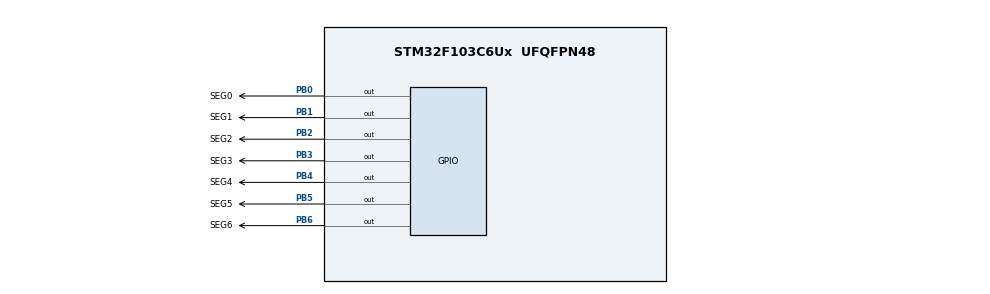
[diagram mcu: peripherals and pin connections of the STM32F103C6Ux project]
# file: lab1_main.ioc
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Mcu.Family=STM32F1
Mcu.Name=STM32F103C6Ux
Mcu.Package=UFQFPN48
NVIC.PriorityGroup=NVIC_PRIORITYGROUP_4
PB0.GPIO_Label=SEG0
PB0.Signal=GPIO_Output
PB1.GPIO_Label=SEG1
PB1.Signal=GPIO_Output
PB2.GPIO_Label=SEG2
PB2.Signal=GPIO_Output
PB3.GPIO_Label=SEG3
PB3.Signal=GPIO_Output
PB4.GPIO_Label=SEG4
PB4.Signal=GPIO_Output
PB5.GPIO_Label=SEG5
PB5.Signal=GPIO_Output
PB6.GPIO_Label=SEG6
PB6.Signal=GPIO_Output
ProjectManager.HeapSize=0x200
ProjectManager.StackSize=0x400
ProjectManager.TargetToolchain=STM32CubeIDE
RCC.APB1Freq_Value=8000000
RCC.APB2Freq_Value=8000000
VP_SYS_VS_ND.Mode=No_Debug
board=custom

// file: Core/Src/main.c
/* USER CODE BEGIN Header */
/**
  ******************************************************************************
  * @file           : main.c
  * @brief          : Main program body
  ******************************************************************************
  * @attention
  *
  * <h2><center>&copy; Copyright (c) 2023 STMicroelectronics.
  * All rights reserved.</center></h2>
  *
  * This software component is licensed by ST under BSD 3-Clause license,
  * the "License"; You may not use this file except in compliance with the
  * License. You may obtain a copy of the License at:
  *                        opensource.org/licenses/BSD-3-Clause
  *
  ******************************************************************************
  */
/* USER CODE END Header */
#include "main.h"

void SystemClock_Config(void);
static void MX_GPIO_Init(void);

void display7SEG(int num, uint16_t *pins){

	switch(num){
	case 0:
		HAL_GPIO_WritePin(GPIOB, pins[0], GPIO_PIN_RESET);
		HAL_GPIO_WritePin(GPIOB, pins[1], GPIO_PIN_RESET);
		HAL_GPIO_WritePin(GPIOB, pins[2], GPIO_PIN_RESET);
		HAL_GPIO_WritePin(GPIOB, pins[3], GPIO_PIN_RESET);
		HAL_GPIO_WritePin(GPIOB, pins[4], GPIO_PIN_RESET);
		HAL_GPIO_WritePin(GPIOB, pins[5], GPIO_PIN_RESET);
		HAL_GPIO_WritePin(GPIOB, pins[6], GPIO_PIN_SET);
		break;
	case 1:
		HAL_GPIO_WritePin(GPIOB, pins[0], GPIO_PIN_SET);
		HAL_GPIO_WritePin(GPIOB, pins[1], GPIO_PIN_RESET);
		HAL_GPIO_WritePin(GPIOB, pins[2], GPIO_PIN_RESET);
		HAL_GPIO_WritePin(GPIOB, pins[3], GPIO_PIN_SET);
		HAL_GPIO_WritePin(GPIOB, pins[4], GPIO_PIN_SET);
		HAL_GPIO_WritePin(GPIOB, pins[5], GPIO_PIN_SET);
		HAL_GPIO_WritePin(GPIOB, pins[6], GPIO_PIN_SET);
		break;
	case 2:
		HAL_GPIO_WritePin(GPIOB, pins[0], GPIO_PIN_RESET);
		HAL_GPIO_WritePin(GPIOB, pins[1], GPIO_PIN_RESET);
		HAL_GPIO_WritePin(GPIOB, pins[2], GPIO_PIN_SET);
		HAL_GPIO_WritePin(GPIOB, pins[3], GPIO_PIN_RESET);
		HAL_GPIO_WritePin(GPIOB, pins[4], GPIO_PIN_RESET);
		HAL_GPIO_WritePin(GPIOB, pins[5], GPIO_PIN_SET);
		HAL_GPIO_WritePin(GPIOB, pins[6], GPIO_PIN_RESET);
		break;
	case 3:
		HAL_GPIO_WritePin(GPIOB, pins[0], GPIO_PIN_RESET);
		HAL_GPIO_WritePin(GPIOB, pins[1], GPIO_PIN_RESET);
		HAL_GPIO_WritePin(GPIOB, pins[2], GPIO_PIN_RESET);
		HAL_GPIO_WritePin(GPIOB, pins[3], GPIO_PIN_RESET);
		HAL_GPIO_WritePin(GPIOB, pins[4], GPIO_PIN_SET);
		HAL_GPIO_WritePin(GPIOB, pins[5], GPIO_PIN_SET);
		HAL_GPIO_WritePin(GPIOB, pins[6], GPIO_PIN_RESET);
		break;
	case 4:
		HAL_GPIO_WritePin(GPIOB, pins[0], GPIO_PIN_SET);
		HAL_GPIO_WritePin(GPIOB, pins[1], GPIO_PIN_RESET);
		HAL_GPIO_WritePin(GPIOB, pins[2], GPIO_PIN_RESET);
		HAL_GPIO_WritePin(GPIOB, pins[3], GPIO_PIN_SET);
		HAL_GPIO_WritePin(GPIOB, pins[4], GPIO_PIN_SET);
		HAL_GPIO_WritePin(GPIOB, pins[5], GPIO_PIN_RESET);
		HAL_GPIO_WritePin(GPIOB, pins[6], GPIO_PIN_RESET);
		break;
	case 5:
		HAL_GPIO_WritePin(GPIOB, pins[0], GPIO_PIN_RESET);
		HAL_GPIO_WritePin(GPIOB, pins[1], GPIO_PIN_SET);
		HAL_GPIO_WritePin(GPIOB, pins[2], GPIO_PIN_RESET);
		HAL_GPIO_WritePin(GPIOB, pins[3], GPIO_PIN_RESET);
		HAL_GPIO_WritePin(GPIOB, pins[4], GPIO_PIN_SET);
		HAL_GPIO_WritePin(GPIOB, pins[5], GPIO_PIN_RESET);
		HAL_GPIO_WritePin(GPIOB, pins[6], GPIO_PIN_RESET);
		break;
	case 6:
		HAL_GPIO_WritePin(GPIOB, pins[0], GPIO_PIN_RESET);
		HAL_GPIO_WritePin(GPIOB, pins[1], GPIO_PIN_SET);
		HAL_GPIO_WritePin(GPIOB, pins[2], GPIO_PIN_RESET);
		HAL_GPIO_WritePin(GPIOB, pins[3], GPIO_PIN_RESET);
		HAL_GPIO_WritePin(GPIOB, pins[4], GPIO_PIN_RESET);
		HAL_GPIO_WritePin(GPIOB, pins[5], GPIO_PIN_RESET);
		HAL_GPIO_WritePin(GPIOB, pins[6], GPIO_PIN_RESET);
		break;
	case 7:
		HAL_GPIO_WritePin(GPIOB, pins[0], GPIO_PIN_RESET);
		HAL_GPIO_WritePin(GPIOB, pins[1], GPIO_PIN_RESET);
		HAL_GPIO_WritePin(GPIOB, pins[2], GPIO_PIN_RESET);
		HAL_GPIO_WritePin(GPIOB, pins[3], GPIO_PIN_SET);
		HAL_GPIO_WritePin(GPIOB, pins[4], GPIO_PIN_SET);
		HAL_GPIO_WritePin(GPIOB, pins[5], GPIO_PIN_SET);
		HAL_GPIO_WritePin(GPIOB, pins[6], GPIO_PIN_SET);
		break;
	case 8:
		HAL_GPIO_WritePin(GPIOB, pins[0], GPIO_PIN_RESET);
		HAL_GPIO_WritePin(GPIOB, pins[1], GPIO_PIN_RESET);
		HAL_GPIO_WritePin(GPIOB, pins[2], GPIO_PIN_RESET);
		HAL_GPIO_WritePin(GPIOB, pins[3], GPIO_PIN_RESET);
		HAL_GPIO_WritePin(GPIOB, pins[4], GPIO_PIN_RESET);
		HAL_GPIO_WritePin(GPIOB, pins[5], GPIO_PIN_RESET);
		HAL_GPIO_WritePin(GPIOB, pins[6], GPIO_PIN_RESET);
		break;
	case 9:
		HAL_GPIO_WritePin(GPIOB, pins[0], GPIO_PIN_RESET);
		HAL_GPIO_WritePin(GPIOB, pins[1], GPIO_PIN_RESET);
		HAL_GPIO_WritePin(GPIOB, pins[2], GPIO_PIN_RESET);
		HAL_GPIO_WritePin(GPIOB, pins[3], GPIO_PIN_RESET);
		HAL_GPIO_WritePin(GPIOB, pins[4], GPIO_PIN_SET);
		HAL_GPIO_WritePin(GPIOB, pins[5], GPIO_PIN_RESET);
		HAL_GPIO_WritePin(GPIOB, pins[6], GPIO_PIN_RESET);
		break;
	default:
		break;
	}
}
int main(void)
{

  /* MCU Configuration--------------------------------------------------------*/

  /* Reset of all peripherals, Initializes the Flash interface and the Systick. */
  HAL_Init();

  /* Configure the system clock */
  SystemClock_Config();

  /* Initialize all configured peripherals */
  MX_GPIO_Init();

  /* Infinite loop */
  /* USER CODE BEGIN WHILE */
  enum lightState {RED1_GREEN2, RED1_YELLOW2, GREEN1_RED2, YELLOW1_RED2,};
  enum lightState curr_state = RED1_GREEN2;
  enum lightState next_state = curr_state;
  uint16_t p_pins[7] = {P0_Pin, P1_Pin, P2_Pin, P3_Pin, P4_Pin, P5_Pin, P6_Pin};
  uint16_t l_pins[7] = {L0_Pin, L1_Pin, L2_Pin, L3_Pin, L4_Pin, L5_Pin, L6_Pin};
  int l_count = 4, p_count = 2, count = 3;
  HAL_GPIO_WritePin(GPIOA, RED1_Pin, SET);
  HAL_GPIO_WritePin(GPIOA, YELLOW1_Pin, SET);
  HAL_GPIO_WritePin(GPIOA, GREEN1_Pin, SET);
  HAL_GPIO_WritePin(GPIOA, RED2_Pin, SET);
  HAL_GPIO_WritePin(GPIOA, YELLOW2_Pin, SET);
  HAL_GPIO_WritePin(GPIOA, GREEN2_Pin, SET);
   while (1)
   {
	   display7SEG(l_count, l_pins);
	   display7SEG(p_count, p_pins);
	   if(count > 0) count --;
	   if(l_count > 0) l_count --;
	   if(p_count > 0) p_count --;
	  switch(curr_state){
	  case RED1_GREEN2:
		  HAL_GPIO_WritePin(RED1_GPIO_Port, RED1_Pin, GPIO_PIN_RESET);
		  HAL_GPIO_WritePin(YELLOW1_GPIO_Port, YELLOW1_Pin, GPIO_PIN_SET);
		  HAL_GPIO_WritePin(GREEN1_GPIO_Port, GREEN1_Pin, GPIO_PIN_SET);
		  HAL_GPIO_WritePin(RED2_GPIO_Port, RED2_Pin, GPIO_PIN_SET);
		  HAL_GPIO_WritePin(YELLOW2_GPIO_Port, YELLOW2_Pin, GPIO_PIN_SET);
		  HAL_GPIO_WritePin(GREEN2_GPIO_Port, GREEN2_Pin, GPIO_PIN_RESET);
		  if(count <= 0){
			  count = 2;
			  next_state = RED1_YELLOW2;
			  p_count = 1;
		  }
		  break;
	  case RED1_YELLOW2:
		  HAL_GPIO_WritePin(RED1_GPIO_Port, RED1_Pin, GPIO_PIN_RESET);
		  HAL_GPIO_WritePin(YELLOW1_GPIO_Port, YELLOW1_Pin, GPIO_PIN_SET);
		  HAL_GPIO_WritePin(GREEN1_GPIO_Port, GREEN1_Pin, GPIO_PIN_SET);
		  HAL_GPIO_WritePin(RED2_GPIO_Port, RED2_Pin, GPIO_PIN_SET);
		  HAL_GPIO_WritePin(YELLOW2_GPIO_Port, YELLOW2_Pin, GPIO_PIN_RESET);
		  HAL_GPIO_WritePin(GREEN2_GPIO_Port, GREEN2_Pin, GPIO_PIN_SET);
		  if(count <= 0){
			  count = 3;
			  next_state = GREEN1_RED2;
			  p_count = 4;
			  l_count = 2;
		  }
		  break;
	  case GREEN1_RED2:
		  HAL_GPIO_WritePin(RED1_GPIO_Port, RED1_Pin, GPIO_PIN_SET);
		  HAL_GPIO_WritePin(YELLOW1_GPIO_Port, YELLOW1_Pin, GPIO_PIN_SET);
		  HAL_GPIO_WritePin(GREEN1_GPIO_Port, GREEN1_Pin, GPIO_PIN_RESET);
		  HAL_GPIO_WritePin(RED2_GPIO_Port, RED2_Pin, GPIO_PIN_RESET);
		  HAL_GPIO_WritePin(YELLOW2_GPIO_Port, YELLOW2_Pin, GPIO_PIN_SET);
		  HAL_GPIO_WritePin(GREEN2_GPIO_Port, GREEN2_Pin, GPIO_PIN_SET);
		  if(count <= 0){
			  count = 2;
			  next_state = YELLOW1_RED2;
			  l_count = 1;
		  }
		  break;
	  case YELLOW1_RED2:
		  HAL_GPIO_WritePin(RED1_GPIO_Port, RED1_Pin, GPIO_PIN_SET);
		  HAL_GPIO_WritePin(YELLOW1_GPIO_Port, YELLOW1_Pin, GPIO_PIN_RESET);
		  HAL_GPIO_WritePin(GREEN1_GPIO_Port, GREEN1_Pin, GPIO_PIN_SET);
		  HAL_GPIO_WritePin(RED2_GPIO_Port, RED2_Pin, GPIO_PIN_RESET);
		  HAL_GPIO_WritePin(YELLOW2_GPIO_Port, YELLOW2_Pin, GPIO_PIN_SET);
		  HAL_GPIO_WritePin(GREEN2_GPIO_Port, GREEN2_Pin, GPIO_PIN_SET);
		  if(count <= 0){
			  count = 3;
			  next_state = RED1_GREEN2;
			  p_count = 2;
			  l_count = 4;
		  }
		  break;
	  default:
		  break;
	  }
	  curr_state = next_state;
	 HAL_Delay(1000);
    /* USER CODE END WHILE */

  }
}

void SystemClock_Config(void)
{
  RCC_OscInitTypeDef RCC_OscInitStruct = {0};
  RCC_ClkInitTypeDef RCC_ClkInitStruct = {0};

  /** Initializes the RCC Oscillators according to the specified parameters
  * in the RCC_OscInitTypeDef structure.
  */
  RCC_OscInitStruct.OscillatorType = RCC_OSCILLATORTYPE_HSI;
  RCC_OscInitStruct.HSIState = RCC_HSI_ON;
  RCC_OscInitStruct.HSICalibrationValue = RCC_HSICALIBRATION_DEFAULT;
  RCC_OscInitStruct.PLL.PLLState = RCC_PLL_NONE;
  if (HAL_RCC_OscConfig(&RCC_OscInitStruct) != HAL_OK)
  {
    Error_Handler();
  }
  /** Initializes the CPU, AHB and APB buses clocks
  */
  RCC_ClkInitStruct.ClockType = RCC_CLOCKTYPE_HCLK|RCC_CLOCKTYPE_SYSCLK
                              |RCC_CLOCKTYPE_PCLK1|RCC_CLOCKTYPE_PCLK2;
  RCC_ClkInitStruct.SYSCLKSource = RCC_SYSCLKSOURCE_HSI;
  RCC_ClkInitStruct.AHBCLKDivider = RCC_SYSCLK_DIV1;
  RCC_ClkInitStruct.APB1CLKDivider = RCC_HCLK_DIV1;
  RCC_ClkInitStruct.APB2CLKDivider = RCC_HCLK_DIV1;

  if (HAL_RCC_ClockConfig(&RCC_ClkInitStruct, FLASH_LATENCY_0) != HAL_OK)
  {
    Error_Handler();
  }
}

static void MX_GPIO_Init(void)
{
  GPIO_InitTypeDef GPIO_InitStruct = {0};

  /* GPIO Ports Clock Enable */
  __HAL_RCC_GPIOA_CLK_ENABLE();
  __HAL_RCC_GPIOB_CLK_ENABLE();

  /*Configure GPIO pin Output Level */
  HAL_GPIO_WritePin(GPIOA, RED1_Pin|YELLOW1_Pin|GREEN1_Pin|RED2_Pin
                          |YELLOW2_Pin|GREEN2_Pin, GPIO_PIN_RESET);

  /*Configure GPIO pin Output Level */
  HAL_GPIO_WritePin(GPIOB, L0_Pin|L1_Pin|L2_Pin|P3_Pin
                          |P4_Pin|P5_Pin|P6_Pin|L3_Pin
                          |L4_Pin|L5_Pin|L6_Pin|P0_Pin
                          |P1_Pin|P2_Pin, GPIO_PIN_RESET);

  /*Configure GPIO pins : RED1_Pin YELLOW1_Pin GREEN1_Pin RED2_Pin
                           YELLOW2_Pin GREEN2_Pin */
  GPIO_InitStruct.Pin = RED1_Pin|YELLOW1_Pin|GREEN1_Pin|RED2_Pin
                          |YELLOW2_Pin|GREEN2_Pin;
  GPIO_InitStruct.Mode = GPIO_MODE_OUTPUT_PP;
  GPIO_InitStruct.Pull = GPIO_NOPULL;
  GPIO_InitStruct.Speed = GPIO_SPEED_FREQ_LOW;
  HAL_GPIO_Init(GPIOA, &GPIO_InitStruct);

  /*Configure GPIO pins : L0_Pin L1_Pin L2_Pin P3_Pin
                           P4_Pin P5_Pin P6_Pin L3_Pin
                           L4_Pin L5_Pin L6_Pin P0_Pin
                           P1_Pin P2_Pin */
  GPIO_InitStruct.Pin = L0_Pin|L1_Pin|L2_Pin|P3_Pin
                          |P4_Pin|P5_Pin|P6_Pin|L3_Pin
                          |L4_Pin|L5_Pin|L6_Pin|P0_Pin
                          |P1_Pin|P2_Pin;
  GPIO_InitStruct.Mode = GPIO_MODE_OUTPUT_PP;
  GPIO_InitStruct.Pull = GPIO_NOPULL;
  GPIO_InitStruct.Speed = GPIO_SPEED_FREQ_LOW;
  HAL_GPIO_Init(GPIOB, &GPIO_InitStruct);

}

void Error_Handler(void)
{
  __disable_irq();
  while (1)
  {
  }
}

/************************ (C) COPYRIGHT STMicroelectronics *****END OF FILE****/
